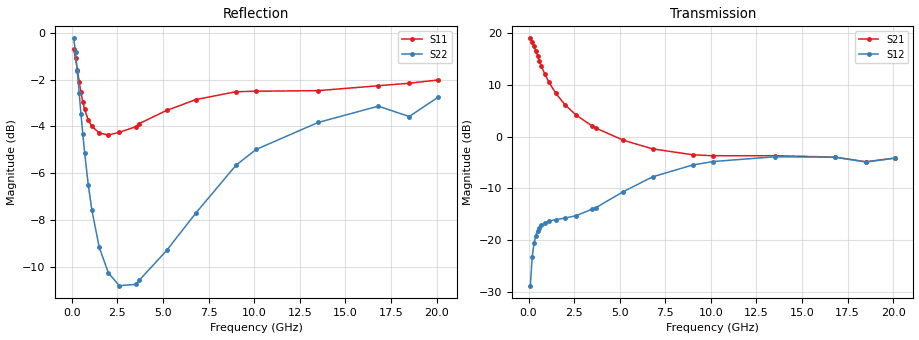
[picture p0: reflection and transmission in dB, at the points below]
!  Infineon Technologies AG
! BFR380L3 , PF131585-7, No.6, Th 09.10.01, soldered on pcb-board, measured with PP GSG850
!  Vce=1.0 V,  Ic=2.5 mA
! Common Emitter S-Parameters:  15. November 2001
#  GHz  S  MA  R  50
! f  S11  S21  S12  S22
! GHz  Mag  Ang  Mag  Ang  Mag  Ang  Mag  Ang
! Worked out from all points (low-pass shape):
!   201 points, 100 MHz to 20.1 GHz, reference 50 ohm
!   highest |S21| = 18.95 dB at 100 MHz (marker M1); lowest = -4.9 dB at 18.5 GHz (marker M2)
!   |S21| within 3 dB of the highest: start of sweep to 454.6 MHz
!   lowest |S11| = -4.4 dB at 2 GHz (marker M3), VSWR 4.06, Z = 12.3 - j1.86 ohm
!   |S11| at or under -10 dB: nowhere
!   |S22| runs from -10.9 to -0.2 dB; largest |S21 - S12| = 8.9
!   S11 on the Smith chart (normalised r, x): 100 MHz: 1.08, -4.98; 400 MHz: 0.30, -1.22; 1.1 GHz: 0.25, -0.34; 3.7 GHz: 0.24, +0.27; 9 GHz: 0.31, +1.06; 20.1 GHz: 0.98, +2.57
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0.1  0.9228 -21.7  8.863 165.2  0.03636 76.2  0.9723 -13.0
0.2  0.8809 -42.3  8.179 151.8  0.06865 66.4  0.9089 -24.9
0.3  0.8343 -60.9  7.439 140.1  0.09291 57.0  0.827 -34.7
0.4  0.7859 -76.7  6.672 130.3  0.1104 50.0  0.7444 -42.7
0.5  0.7457 -90.1  5.961 122.1  0.123 44.5  0.6708 -49.2
0.6  0.7121 -101.7  5.336 115.3  0.1321 40.3  0.6078 -54.3
0.7  0.6858 -111.6  4.816 109.3  0.1387 36.9  0.5548 -58.5
0.9  0.6511 -127.6  3.987 99.8  0.1472 32.4  0.4737 -65.0
1.1  0.6312 -140.1  3.394 92.0  0.1524 29.8  0.4181 -70.2
1.5  0.6111 -158.8  2.606 79.8  0.1578 28.0  0.3488 -78.2
2  0.605 -175.5  2.028 67.7  0.1633 29.1  0.3076 -87.0
2.6  0.613 169.3  1.616 55.7  0.1722 32.8  0.2888 -97.9
3.5  0.6301 151.2  1.26 40.9  0.1993 39.6  0.2907 -114.9
3.7  0.6402 148.1  1.205 38.2  0.2062 40.5  0.2967 -119.5
5.2  0.6826 125.0  0.9215 20.6  0.2941 42.8  0.3434 -148.8
6.8  0.72 104.6  0.7607 8.9  0.4082 36.1  0.4126 -179.9
8.999999  0.7483 84.1  0.6671 -0.5  0.5317 20.3  0.5216 147.2
10.1  0.7501 76.0  0.6528 -4.6  0.5736 12.1  0.5636 132.6
13.5  0.7523 58.4  0.6531 -18.8  0.6382 -10.7  0.6434 98.8
16.8  0.7705 46.9  0.6335 -31.0  0.6319 -27.0  0.697 76.0
18.5  0.7802 45.2  0.5712 -39.0  0.5672 -35.5  0.6625 70.4
20.1  0.7928 38.1  0.6203 -42.9  0.6193 -40.4  0.7293 59.6
